VERSION 5.7 ;
  NOWIREEXTENSIONATPIN ON ;
  DIVIDERCHAR "/" ;
  BUSBITCHARS "[]" ;
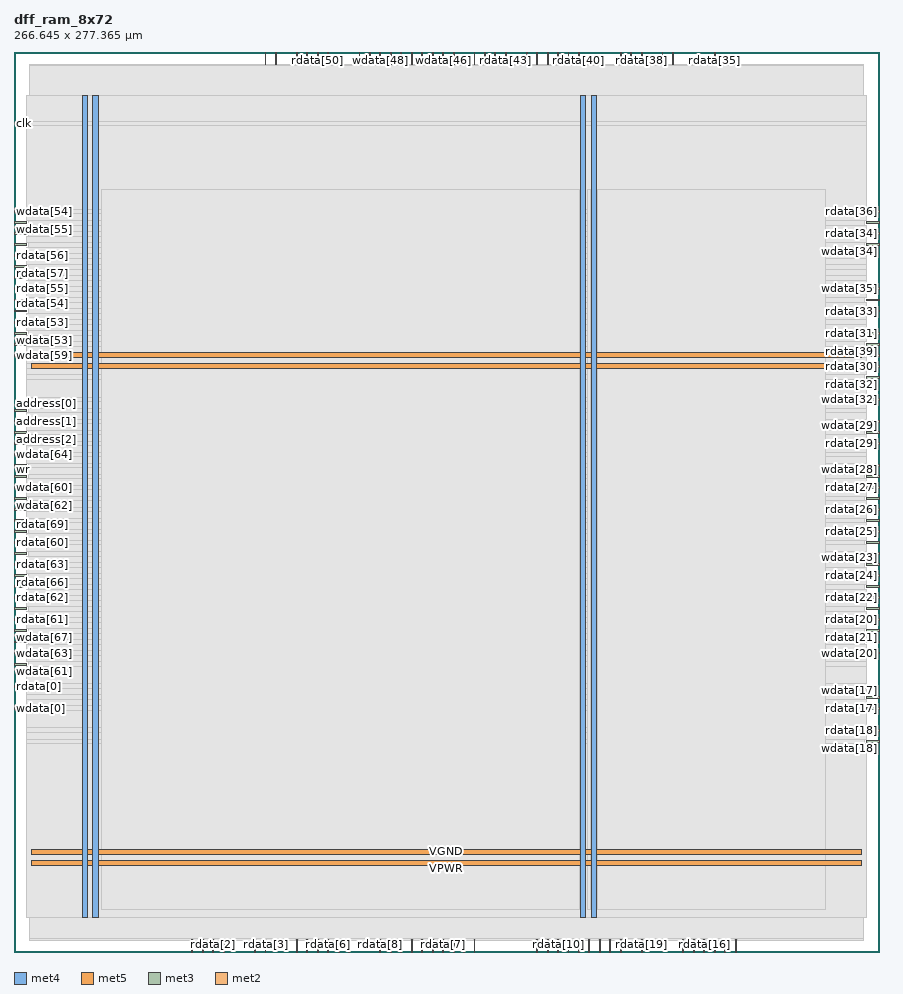
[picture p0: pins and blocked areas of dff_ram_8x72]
MACRO dff_ram_8x72
  CLASS BLOCK ;
  FOREIGN dff_ram_8x72 ;
  ORIGIN 0.000 0.000 ;
  SIZE 266.645 BY 277.365 ;
  PIN VGND
    DIRECTION INOUT ;
    USE GROUND ;
    PORT
      LAYER met4 ;
        RECT 24.340 10.640 25.940 264.080 ;
    END
    PORT
      LAYER met4 ;
        RECT 177.940 10.640 179.540 264.080 ;
    END
    PORT
      LAYER met5 ;
        RECT 5.280 30.030 261.060 31.630 ;
    END
    PORT
      LAYER met5 ;
        RECT 5.280 183.210 261.060 184.810 ;
    END
  END VGND
  PIN VPWR
    DIRECTION INOUT ;
    USE POWER ;
    PORT
      LAYER met4 ;
        RECT 21.040 10.640 22.640 264.080 ;
    END
    PORT
      LAYER met4 ;
        RECT 174.640 10.640 176.240 264.080 ;
    END
    PORT
      LAYER met5 ;
        RECT 5.280 26.730 261.060 28.330 ;
    END
    PORT
      LAYER met5 ;
        RECT 5.280 179.910 261.060 181.510 ;
    END
  END VPWR
  PIN address[0]
    DIRECTION INPUT ;
    USE SIGNAL ;
    ANTENNAGATEAREA 0.213000 ;
    PORT
      LAYER met3 ;
        RECT 0.000 166.640 4.000 167.240 ;
    END
  END address[0]
  PIN address[1]
    DIRECTION INPUT ;
    USE SIGNAL ;
    ANTENNAGATEAREA 0.159000 ;
    PORT
      LAYER met3 ;
        RECT 0.000 163.240 4.000 163.840 ;
    END
  END address[1]
  PIN address[2]
    DIRECTION INPUT ;
    USE SIGNAL ;
    ANTENNAGATEAREA 0.126000 ;
    PORT
      LAYER met3 ;
        RECT 0.000 159.840 4.000 160.440 ;
    END
  END address[2]
  PIN clk
    DIRECTION INPUT ;
    USE SIGNAL ;
    ANTENNAGATEAREA 0.852000 ;
    PORT
      LAYER met3 ;
        RECT 0.000 255.040 4.000 255.640 ;
    END
  END clk
  PIN rdata[0]
    DIRECTION OUTPUT TRISTATE ;
    USE SIGNAL ;
    ANTENNADIFFAREA 0.795200 ;
    PORT
      LAYER met3 ;
        RECT 0.000 81.640 4.000 82.240 ;
    END
  END rdata[0]
  PIN rdata[10]
    DIRECTION OUTPUT TRISTATE ;
    USE SIGNAL ;
    ANTENNADIFFAREA 0.795200 ;
    PORT
      LAYER met2 ;
        RECT 167.530 0.000 167.810 4.000 ;
    END
  END rdata[10]
  PIN rdata[11]
    DIRECTION OUTPUT TRISTATE ;
    USE SIGNAL ;
    ANTENNADIFFAREA 0.795200 ;
    PORT
      LAYER met2 ;
        RECT 177.190 0.000 177.470 4.000 ;
    END
  END rdata[11]
  PIN rdata[12]
    DIRECTION OUTPUT TRISTATE ;
    USE SIGNAL ;
    ANTENNADIFFAREA 0.795200 ;
    PORT
      LAYER met2 ;
        RECT 170.750 0.000 171.030 4.000 ;
    END
  END rdata[12]
  PIN rdata[13]
    DIRECTION OUTPUT TRISTATE ;
    USE SIGNAL ;
    ANTENNADIFFAREA 0.795200 ;
    PORT
      LAYER met2 ;
        RECT 219.050 0.000 219.330 4.000 ;
    END
  END rdata[13]
  PIN rdata[14]
    DIRECTION OUTPUT TRISTATE ;
    USE SIGNAL ;
    ANTENNADIFFAREA 0.795200 ;
    PORT
      LAYER met2 ;
        RECT 215.830 0.000 216.110 4.000 ;
    END
  END rdata[14]
  PIN rdata[15]
    DIRECTION OUTPUT TRISTATE ;
    USE SIGNAL ;
    ANTENNADIFFAREA 0.795200 ;
    PORT
      LAYER met2 ;
        RECT 173.970 0.000 174.250 4.000 ;
    END
  END rdata[15]
  PIN rdata[16]
    DIRECTION OUTPUT TRISTATE ;
    USE SIGNAL ;
    ANTENNADIFFAREA 0.795200 ;
    PORT
      LAYER met2 ;
        RECT 212.610 0.000 212.890 4.000 ;
    END
  END rdata[16]
  PIN rdata[17]
    DIRECTION OUTPUT TRISTATE ;
    USE SIGNAL ;
    ANTENNADIFFAREA 0.795200 ;
    PORT
      LAYER met3 ;
        RECT 262.645 74.840 266.645 75.440 ;
    END
  END rdata[17]
  PIN rdata[18]
    DIRECTION OUTPUT TRISTATE ;
    USE SIGNAL ;
    ANTENNADIFFAREA 0.795200 ;
    PORT
      LAYER met3 ;
        RECT 262.645 68.040 266.645 68.640 ;
    END
  END rdata[18]
  PIN rdata[19]
    DIRECTION OUTPUT TRISTATE ;
    USE SIGNAL ;
    ANTENNADIFFAREA 0.795200 ;
    PORT
      LAYER met2 ;
        RECT 193.290 0.000 193.570 4.000 ;
    END
  END rdata[19]
  PIN rdata[1]
    DIRECTION OUTPUT TRISTATE ;
    USE SIGNAL ;
    ANTENNADIFFAREA 0.795200 ;
    PORT
      LAYER met2 ;
        RECT 64.490 0.000 64.770 4.000 ;
    END
  END rdata[1]
  PIN rdata[20]
    DIRECTION OUTPUT TRISTATE ;
    USE SIGNAL ;
    ANTENNADIFFAREA 0.795200 ;
    PORT
      LAYER met3 ;
        RECT 262.645 102.040 266.645 102.640 ;
    END
  END rdata[20]
  PIN rdata[21]
    DIRECTION OUTPUT TRISTATE ;
    USE SIGNAL ;
    ANTENNADIFFAREA 0.445500 ;
    PORT
      LAYER met3 ;
        RECT 262.645 98.640 266.645 99.240 ;
    END
  END rdata[21]
  PIN rdata[22]
    DIRECTION OUTPUT TRISTATE ;
    USE SIGNAL ;
    ANTENNADIFFAREA 0.445500 ;
    PORT
      LAYER met3 ;
        RECT 262.645 108.840 266.645 109.440 ;
    END
  END rdata[22]
  PIN rdata[23]
    DIRECTION OUTPUT TRISTATE ;
    USE SIGNAL ;
    ANTENNADIFFAREA 0.445500 ;
    PORT
      LAYER met3 ;
        RECT 262.645 122.440 266.645 123.040 ;
    END
  END rdata[23]
  PIN rdata[24]
    DIRECTION OUTPUT TRISTATE ;
    USE SIGNAL ;
    ANTENNADIFFAREA 0.795200 ;
    PORT
      LAYER met3 ;
        RECT 262.645 115.640 266.645 116.240 ;
    END
  END rdata[24]
  PIN rdata[25]
    DIRECTION OUTPUT TRISTATE ;
    USE SIGNAL ;
    ANTENNADIFFAREA 0.795200 ;
    PORT
      LAYER met3 ;
        RECT 262.645 129.240 266.645 129.840 ;
    END
  END rdata[25]
  PIN rdata[26]
    DIRECTION OUTPUT TRISTATE ;
    USE SIGNAL ;
    ANTENNADIFFAREA 0.445500 ;
    PORT
      LAYER met3 ;
        RECT 262.645 136.040 266.645 136.640 ;
    END
  END rdata[26]
  PIN rdata[27]
    DIRECTION OUTPUT TRISTATE ;
    USE SIGNAL ;
    ANTENNADIFFAREA 0.795200 ;
    PORT
      LAYER met3 ;
        RECT 262.645 142.840 266.645 143.440 ;
    END
  END rdata[27]
  PIN rdata[28]
    DIRECTION OUTPUT TRISTATE ;
    USE SIGNAL ;
    ANTENNADIFFAREA 0.445500 ;
    PORT
      LAYER met3 ;
        RECT 262.645 149.640 266.645 150.240 ;
    END
  END rdata[28]
  PIN rdata[29]
    DIRECTION OUTPUT TRISTATE ;
    USE SIGNAL ;
    ANTENNADIFFAREA 0.445500 ;
    PORT
      LAYER met3 ;
        RECT 262.645 156.440 266.645 157.040 ;
    END
  END rdata[29]
  PIN rdata[2]
    DIRECTION OUTPUT TRISTATE ;
    USE SIGNAL ;
    ANTENNADIFFAREA 0.795200 ;
    PORT
      LAYER met2 ;
        RECT 61.270 0.000 61.550 4.000 ;
    END
  END rdata[2]
  PIN rdata[30]
    DIRECTION OUTPUT TRISTATE ;
    USE SIGNAL ;
    ANTENNADIFFAREA 0.795200 ;
    PORT
      LAYER met3 ;
        RECT 262.645 180.240 266.645 180.840 ;
    END
  END rdata[30]
  PIN rdata[31]
    DIRECTION OUTPUT TRISTATE ;
    USE SIGNAL ;
    ANTENNADIFFAREA 0.795200 ;
    PORT
      LAYER met3 ;
        RECT 262.645 190.440 266.645 191.040 ;
    END
  END rdata[31]
  PIN rdata[32]
    DIRECTION OUTPUT TRISTATE ;
    USE SIGNAL ;
    ANTENNADIFFAREA 0.445500 ;
    PORT
      LAYER met3 ;
        RECT 262.645 176.840 266.645 177.440 ;
    END
  END rdata[32]
  PIN rdata[33]
    DIRECTION OUTPUT TRISTATE ;
    USE SIGNAL ;
    ANTENNADIFFAREA 0.445500 ;
    PORT
      LAYER met3 ;
        RECT 262.645 197.240 266.645 197.840 ;
    END
  END rdata[33]
  PIN rdata[34]
    DIRECTION OUTPUT TRISTATE ;
    USE SIGNAL ;
    ANTENNADIFFAREA 0.795200 ;
    PORT
      LAYER met3 ;
        RECT 262.645 221.040 266.645 221.640 ;
    END
  END rdata[34]
  PIN rdata[35]
    DIRECTION OUTPUT TRISTATE ;
    USE SIGNAL ;
    ANTENNADIFFAREA 0.795200 ;
    PORT
      LAYER met2 ;
        RECT 215.830 273.365 216.110 277.365 ;
    END
  END rdata[35]
  PIN rdata[36]
    DIRECTION OUTPUT TRISTATE ;
    USE SIGNAL ;
    ANTENNADIFFAREA 0.445500 ;
    PORT
      LAYER met3 ;
        RECT 262.645 227.840 266.645 228.440 ;
    END
  END rdata[36]
  PIN rdata[37]
    DIRECTION OUTPUT TRISTATE ;
    USE SIGNAL ;
    ANTENNADIFFAREA 0.795200 ;
    PORT
      LAYER met2 ;
        RECT 202.950 273.365 203.230 277.365 ;
    END
  END rdata[37]
  PIN rdata[38]
    DIRECTION OUTPUT TRISTATE ;
    USE SIGNAL ;
    ANTENNADIFFAREA 0.795200 ;
    PORT
      LAYER met2 ;
        RECT 193.290 273.365 193.570 277.365 ;
    END
  END rdata[38]
  PIN rdata[39]
    DIRECTION OUTPUT TRISTATE ;
    USE SIGNAL ;
    ANTENNADIFFAREA 0.445500 ;
    PORT
      LAYER met3 ;
        RECT 262.645 187.040 266.645 187.640 ;
    END
  END rdata[39]
  PIN rdata[3]
    DIRECTION OUTPUT TRISTATE ;
    USE SIGNAL ;
    ANTENNADIFFAREA 0.795200 ;
    PORT
      LAYER met2 ;
        RECT 77.370 0.000 77.650 4.000 ;
    END
  END rdata[3]
  PIN rdata[40]
    DIRECTION OUTPUT TRISTATE ;
    USE SIGNAL ;
    ANTENNADIFFAREA 0.795200 ;
    PORT
      LAYER met2 ;
        RECT 173.970 273.365 174.250 277.365 ;
    END
  END rdata[40]
  PIN rdata[41]
    DIRECTION OUTPUT TRISTATE ;
    USE SIGNAL ;
    ANTENNADIFFAREA 0.795200 ;
    PORT
      LAYER met2 ;
        RECT 157.870 273.365 158.150 277.365 ;
    END
  END rdata[41]
  PIN rdata[42]
    DIRECTION OUTPUT TRISTATE ;
    USE SIGNAL ;
    ANTENNADIFFAREA 0.795200 ;
    PORT
      LAYER met2 ;
        RECT 170.750 273.365 171.030 277.365 ;
    END
  END rdata[42]
  PIN rdata[43]
    DIRECTION OUTPUT TRISTATE ;
    USE SIGNAL ;
    ANTENNADIFFAREA 0.795200 ;
    PORT
      LAYER met2 ;
        RECT 151.430 273.365 151.710 277.365 ;
    END
  END rdata[43]
  PIN rdata[44]
    DIRECTION OUTPUT TRISTATE ;
    USE SIGNAL ;
    ANTENNADIFFAREA 0.795200 ;
    PORT
      LAYER met2 ;
        RECT 148.210 273.365 148.490 277.365 ;
    END
  END rdata[44]
  PIN rdata[45]
    DIRECTION OUTPUT TRISTATE ;
    USE SIGNAL ;
    ANTENNADIFFAREA 0.795200 ;
    PORT
      LAYER met2 ;
        RECT 128.890 273.365 129.170 277.365 ;
    END
  END rdata[45]
  PIN rdata[46]
    DIRECTION OUTPUT TRISTATE ;
    USE SIGNAL ;
    ANTENNADIFFAREA 0.795200 ;
    PORT
      LAYER met2 ;
        RECT 135.330 273.365 135.610 277.365 ;
    END
  END rdata[46]
  PIN rdata[47]
    DIRECTION OUTPUT TRISTATE ;
    USE SIGNAL ;
    ANTENNADIFFAREA 0.795200 ;
    PORT
      LAYER met2 ;
        RECT 122.450 273.365 122.730 277.365 ;
    END
  END rdata[47]
  PIN rdata[48]
    DIRECTION OUTPUT TRISTATE ;
    USE SIGNAL ;
    ANTENNADIFFAREA 0.795200 ;
    PORT
      LAYER met2 ;
        RECT 119.230 273.365 119.510 277.365 ;
    END
  END rdata[48]
  PIN rdata[49]
    DIRECTION OUTPUT TRISTATE ;
    USE SIGNAL ;
    ANTENNADIFFAREA 0.795200 ;
    PORT
      LAYER met2 ;
        RECT 109.570 273.365 109.850 277.365 ;
    END
  END rdata[49]
  PIN rdata[4]
    DIRECTION OUTPUT TRISTATE ;
    USE SIGNAL ;
    ANTENNADIFFAREA 0.795200 ;
    PORT
      LAYER met2 ;
        RECT 87.030 0.000 87.310 4.000 ;
    END
  END rdata[4]
  PIN rdata[50]
    DIRECTION OUTPUT TRISTATE ;
    USE SIGNAL ;
    ANTENNADIFFAREA 0.795200 ;
    PORT
      LAYER met2 ;
        RECT 93.470 273.365 93.750 277.365 ;
    END
  END rdata[50]
  PIN rdata[51]
    DIRECTION OUTPUT TRISTATE ;
    USE SIGNAL ;
    ANTENNADIFFAREA 0.795200 ;
    PORT
      LAYER met2 ;
        RECT 77.370 273.365 77.650 277.365 ;
    END
  END rdata[51]
  PIN rdata[52]
    DIRECTION OUTPUT TRISTATE ;
    USE SIGNAL ;
    ANTENNADIFFAREA 0.795200 ;
    PORT
      LAYER met2 ;
        RECT 90.250 273.365 90.530 277.365 ;
    END
  END rdata[52]
  PIN rdata[53]
    DIRECTION OUTPUT TRISTATE ;
    USE SIGNAL ;
    ANTENNADIFFAREA 0.795200 ;
    PORT
      LAYER met3 ;
        RECT 0.000 193.840 4.000 194.440 ;
    END
  END rdata[53]
  PIN rdata[54]
    DIRECTION OUTPUT TRISTATE ;
    USE SIGNAL ;
    ANTENNADIFFAREA 0.795200 ;
    PORT
      LAYER met3 ;
        RECT 0.000 197.240 4.000 197.840 ;
    END
  END rdata[54]
  PIN rdata[55]
    DIRECTION OUTPUT TRISTATE ;
    USE SIGNAL ;
    ANTENNADIFFAREA 0.795200 ;
    PORT
      LAYER met3 ;
        RECT 0.000 204.040 4.000 204.640 ;
    END
  END rdata[55]
  PIN rdata[56]
    DIRECTION OUTPUT TRISTATE ;
    USE SIGNAL ;
    ANTENNADIFFAREA 0.795200 ;
    PORT
      LAYER met3 ;
        RECT 0.000 214.240 4.000 214.840 ;
    END
  END rdata[56]
  PIN rdata[57]
    DIRECTION OUTPUT TRISTATE ;
    USE SIGNAL ;
    ANTENNADIFFAREA 0.795200 ;
    PORT
      LAYER met3 ;
        RECT 0.000 210.840 4.000 211.440 ;
    END
  END rdata[57]
  PIN rdata[58]
    DIRECTION OUTPUT TRISTATE ;
    USE SIGNAL ;
    ANTENNADIFFAREA 0.795200 ;
    PORT
      LAYER met3 ;
        RECT 0.000 207.440 4.000 208.040 ;
    END
  END rdata[58]
  PIN rdata[59]
    DIRECTION OUTPUT TRISTATE ;
    USE SIGNAL ;
    ANTENNADIFFAREA 0.795200 ;
    PORT
      LAYER met3 ;
        RECT 0.000 200.640 4.000 201.240 ;
    END
  END rdata[59]
  PIN rdata[5]
    DIRECTION OUTPUT TRISTATE ;
    USE SIGNAL ;
    ANTENNADIFFAREA 0.795200 ;
    PORT
      LAYER met2 ;
        RECT 99.910 0.000 100.190 4.000 ;
    END
  END rdata[5]
  PIN rdata[60]
    DIRECTION OUTPUT TRISTATE ;
    USE SIGNAL ;
    ANTENNADIFFAREA 0.795200 ;
    PORT
      LAYER met3 ;
        RECT 0.000 125.840 4.000 126.440 ;
    END
  END rdata[60]
  PIN rdata[61]
    DIRECTION OUTPUT TRISTATE ;
    USE SIGNAL ;
    ANTENNADIFFAREA 0.795200 ;
    PORT
      LAYER met3 ;
        RECT 0.000 102.040 4.000 102.640 ;
    END
  END rdata[61]
  PIN rdata[62]
    DIRECTION OUTPUT TRISTATE ;
    USE SIGNAL ;
    ANTENNADIFFAREA 0.795200 ;
    PORT
      LAYER met3 ;
        RECT 0.000 108.840 4.000 109.440 ;
    END
  END rdata[62]
  PIN rdata[63]
    DIRECTION OUTPUT TRISTATE ;
    USE SIGNAL ;
    ANTENNADIFFAREA 0.795200 ;
    PORT
      LAYER met3 ;
        RECT 0.000 119.040 4.000 119.640 ;
    END
  END rdata[63]
  PIN rdata[64]
    DIRECTION OUTPUT TRISTATE ;
    USE SIGNAL ;
    ANTENNADIFFAREA 0.795200 ;
    PORT
      LAYER met3 ;
        RECT 0.000 122.440 4.000 123.040 ;
    END
  END rdata[64]
  PIN rdata[65]
    DIRECTION OUTPUT TRISTATE ;
    USE SIGNAL ;
    ANTENNADIFFAREA 0.795200 ;
    PORT
      LAYER met3 ;
        RECT 0.000 112.240 4.000 112.840 ;
    END
  END rdata[65]
  PIN rdata[66]
    DIRECTION OUTPUT TRISTATE ;
    USE SIGNAL ;
    ANTENNADIFFAREA 0.795200 ;
    PORT
      LAYER met3 ;
        RECT 0.000 115.640 4.000 116.240 ;
    END
  END rdata[66]
  PIN rdata[67]
    DIRECTION OUTPUT TRISTATE ;
    USE SIGNAL ;
    ANTENNADIFFAREA 0.795200 ;
    PORT
      LAYER met3 ;
        RECT 0.000 132.640 4.000 133.240 ;
    END
  END rdata[67]
  PIN rdata[68]
    DIRECTION OUTPUT TRISTATE ;
    USE SIGNAL ;
    ANTENNADIFFAREA 0.795200 ;
    PORT
      LAYER met3 ;
        RECT 0.000 105.440 4.000 106.040 ;
    END
  END rdata[68]
  PIN rdata[69]
    DIRECTION OUTPUT TRISTATE ;
    USE SIGNAL ;
    ANTENNADIFFAREA 0.795200 ;
    PORT
      LAYER met3 ;
        RECT 0.000 129.240 4.000 129.840 ;
    END
  END rdata[69]
  PIN rdata[6]
    DIRECTION OUTPUT TRISTATE ;
    USE SIGNAL ;
    ANTENNADIFFAREA 0.795200 ;
    PORT
      LAYER met2 ;
        RECT 96.690 0.000 96.970 4.000 ;
    END
  END rdata[6]
  PIN rdata[70]
    DIRECTION OUTPUT TRISTATE ;
    USE SIGNAL ;
    ANTENNADIFFAREA 0.795200 ;
    PORT
      LAYER met2 ;
        RECT 125.670 0.000 125.950 4.000 ;
    END
  END rdata[70]
  PIN rdata[71]
    DIRECTION OUTPUT TRISTATE ;
    USE SIGNAL ;
    ANTENNADIFFAREA 0.795200 ;
    PORT
      LAYER met2 ;
        RECT 141.770 0.000 142.050 4.000 ;
    END
  END rdata[71]
  PIN rdata[7]
    DIRECTION OUTPUT TRISTATE ;
    USE SIGNAL ;
    ANTENNADIFFAREA 0.795200 ;
    PORT
      LAYER met2 ;
        RECT 132.110 0.000 132.390 4.000 ;
    END
  END rdata[7]
  PIN rdata[8]
    DIRECTION OUTPUT TRISTATE ;
    USE SIGNAL ;
    ANTENNADIFFAREA 0.795200 ;
    PORT
      LAYER met2 ;
        RECT 112.790 0.000 113.070 4.000 ;
    END
  END rdata[8]
  PIN rdata[9]
    DIRECTION OUTPUT TRISTATE ;
    USE SIGNAL ;
    ANTENNADIFFAREA 0.795200 ;
    PORT
      LAYER met2 ;
        RECT 135.330 0.000 135.610 4.000 ;
    END
  END rdata[9]
  PIN wdata[0]
    DIRECTION INPUT ;
    USE SIGNAL ;
    ANTENNAGATEAREA 0.196500 ;
    PORT
      LAYER met3 ;
        RECT 0.000 74.840 4.000 75.440 ;
    END
  END wdata[0]
  PIN wdata[10]
    DIRECTION INPUT ;
    USE SIGNAL ;
    ANTENNAGATEAREA 0.196500 ;
    PORT
      LAYER met2 ;
        RECT 161.090 0.000 161.370 4.000 ;
    END
  END wdata[10]
  PIN wdata[11]
    DIRECTION INPUT ;
    USE SIGNAL ;
    ANTENNAGATEAREA 0.196500 ;
    PORT
      LAYER met2 ;
        RECT 180.410 0.000 180.690 4.000 ;
    END
  END wdata[11]
  PIN wdata[12]
    DIRECTION INPUT ;
    USE SIGNAL ;
    ANTENNAGATEAREA 0.196500 ;
    PORT
      LAYER met2 ;
        RECT 164.310 0.000 164.590 4.000 ;
    END
  END wdata[12]
  PIN wdata[13]
    DIRECTION INPUT ;
    USE SIGNAL ;
    ANTENNAGATEAREA 0.196500 ;
    PORT
      LAYER met2 ;
        RECT 222.270 0.000 222.550 4.000 ;
    END
  END wdata[13]
  PIN wdata[14]
    DIRECTION INPUT ;
    USE SIGNAL ;
    ANTENNAGATEAREA 0.196500 ;
    PORT
      LAYER met2 ;
        RECT 209.390 0.000 209.670 4.000 ;
    END
  END wdata[14]
  PIN wdata[15]
    DIRECTION INPUT ;
    USE SIGNAL ;
    ANTENNAGATEAREA 0.196500 ;
    PORT
      LAYER met2 ;
        RECT 186.850 0.000 187.130 4.000 ;
    END
  END wdata[15]
  PIN wdata[16]
    DIRECTION INPUT ;
    USE SIGNAL ;
    ANTENNAGATEAREA 0.196500 ;
    PORT
      LAYER met2 ;
        RECT 206.170 0.000 206.450 4.000 ;
    END
  END wdata[16]
  PIN wdata[17]
    DIRECTION INPUT ;
    USE SIGNAL ;
    ANTENNAGATEAREA 0.196500 ;
    PORT
      LAYER met3 ;
        RECT 262.645 78.240 266.645 78.840 ;
    END
  END wdata[17]
  PIN wdata[18]
    DIRECTION INPUT ;
    USE SIGNAL ;
    ANTENNAGATEAREA 0.196500 ;
    PORT
      LAYER met3 ;
        RECT 262.645 64.640 266.645 65.240 ;
    END
  END wdata[18]
  PIN wdata[19]
    DIRECTION INPUT ;
    USE SIGNAL ;
    ANTENNAGATEAREA 0.196500 ;
    PORT
      LAYER met2 ;
        RECT 183.630 0.000 183.910 4.000 ;
    END
  END wdata[19]
  PIN wdata[1]
    DIRECTION INPUT ;
    USE SIGNAL ;
    ANTENNAGATEAREA 0.196500 ;
    PORT
      LAYER met2 ;
        RECT 58.050 0.000 58.330 4.000 ;
    END
  END wdata[1]
  PIN wdata[20]
    DIRECTION INPUT ;
    USE SIGNAL ;
    ANTENNAGATEAREA 0.196500 ;
    PORT
      LAYER met3 ;
        RECT 262.645 91.840 266.645 92.440 ;
    END
  END wdata[20]
  PIN wdata[21]
    DIRECTION INPUT ;
    USE SIGNAL ;
    ANTENNAGATEAREA 0.196500 ;
    PORT
      LAYER met3 ;
        RECT 262.645 95.240 266.645 95.840 ;
    END
  END wdata[21]
  PIN wdata[22]
    DIRECTION INPUT ;
    USE SIGNAL ;
    ANTENNAGATEAREA 0.196500 ;
    PORT
      LAYER met3 ;
        RECT 262.645 105.440 266.645 106.040 ;
    END
  END wdata[22]
  PIN wdata[23]
    DIRECTION INPUT ;
    USE SIGNAL ;
    ANTENNAGATEAREA 0.196500 ;
    PORT
      LAYER met3 ;
        RECT 262.645 119.040 266.645 119.640 ;
    END
  END wdata[23]
  PIN wdata[24]
    DIRECTION INPUT ;
    USE SIGNAL ;
    ANTENNAGATEAREA 0.196500 ;
    PORT
      LAYER met3 ;
        RECT 262.645 112.240 266.645 112.840 ;
    END
  END wdata[24]
  PIN wdata[25]
    DIRECTION INPUT ;
    USE SIGNAL ;
    ANTENNAGATEAREA 0.196500 ;
    PORT
      LAYER met3 ;
        RECT 262.645 125.840 266.645 126.440 ;
    END
  END wdata[25]
  PIN wdata[26]
    DIRECTION INPUT ;
    USE SIGNAL ;
    ANTENNAGATEAREA 0.196500 ;
    PORT
      LAYER met3 ;
        RECT 262.645 132.640 266.645 133.240 ;
    END
  END wdata[26]
  PIN wdata[27]
    DIRECTION INPUT ;
    USE SIGNAL ;
    ANTENNAGATEAREA 0.196500 ;
    PORT
      LAYER met3 ;
        RECT 262.645 139.440 266.645 140.040 ;
    END
  END wdata[27]
  PIN wdata[28]
    DIRECTION INPUT ;
    USE SIGNAL ;
    ANTENNAGATEAREA 0.196500 ;
    PORT
      LAYER met3 ;
        RECT 262.645 146.240 266.645 146.840 ;
    END
  END wdata[28]
  PIN wdata[29]
    DIRECTION INPUT ;
    USE SIGNAL ;
    ANTENNAGATEAREA 0.196500 ;
    PORT
      LAYER met3 ;
        RECT 262.645 159.840 266.645 160.440 ;
    END
  END wdata[29]
  PIN wdata[2]
    DIRECTION INPUT ;
    USE SIGNAL ;
    ANTENNAGATEAREA 0.196500 ;
    PORT
      LAYER met2 ;
        RECT 54.830 0.000 55.110 4.000 ;
    END
  END wdata[2]
  PIN wdata[30]
    DIRECTION INPUT ;
    USE SIGNAL ;
    ANTENNAGATEAREA 0.196500 ;
    PORT
      LAYER met3 ;
        RECT 262.645 163.240 266.645 163.840 ;
    END
  END wdata[30]
  PIN wdata[31]
    DIRECTION INPUT ;
    USE SIGNAL ;
    ANTENNAGATEAREA 0.196500 ;
    PORT
      LAYER met3 ;
        RECT 262.645 183.640 266.645 184.240 ;
    END
  END wdata[31]
  PIN wdata[32]
    DIRECTION INPUT ;
    USE SIGNAL ;
    ANTENNAGATEAREA 0.196500 ;
    PORT
      LAYER met3 ;
        RECT 262.645 170.040 266.645 170.640 ;
    END
  END wdata[32]
  PIN wdata[33]
    DIRECTION INPUT ;
    USE SIGNAL ;
    ANTENNAGATEAREA 0.196500 ;
    PORT
      LAYER met3 ;
        RECT 262.645 200.640 266.645 201.240 ;
    END
  END wdata[33]
  PIN wdata[34]
    DIRECTION INPUT ;
    USE SIGNAL ;
    ANTENNAGATEAREA 0.196500 ;
    PORT
      LAYER met3 ;
        RECT 262.645 217.640 266.645 218.240 ;
    END
  END wdata[34]
  PIN wdata[35]
    DIRECTION INPUT ;
    USE SIGNAL ;
    ANTENNAGATEAREA 0.196500 ;
    PORT
      LAYER met3 ;
        RECT 262.645 204.040 266.645 204.640 ;
    END
  END wdata[35]
  PIN wdata[36]
    DIRECTION INPUT ;
    USE SIGNAL ;
    ANTENNAGATEAREA 0.196500 ;
    PORT
      LAYER met3 ;
        RECT 262.645 224.440 266.645 225.040 ;
    END
  END wdata[36]
  PIN wdata[37]
    DIRECTION INPUT ;
    USE SIGNAL ;
    ANTENNAGATEAREA 0.196500 ;
    PORT
      LAYER met2 ;
        RECT 199.730 273.365 200.010 277.365 ;
    END
  END wdata[37]
  PIN wdata[38]
    DIRECTION INPUT ;
    USE SIGNAL ;
    ANTENNAGATEAREA 0.196500 ;
    PORT
      LAYER met2 ;
        RECT 190.070 273.365 190.350 277.365 ;
    END
  END wdata[38]
  PIN wdata[39]
    DIRECTION INPUT ;
    USE SIGNAL ;
    ANTENNAGATEAREA 0.196500 ;
    PORT
      LAYER met2 ;
        RECT 186.850 273.365 187.130 277.365 ;
    END
  END wdata[39]
  PIN wdata[3]
    DIRECTION INPUT ;
    USE SIGNAL ;
    ANTENNAGATEAREA 0.196500 ;
    PORT
      LAYER met2 ;
        RECT 74.150 0.000 74.430 4.000 ;
    END
  END wdata[3]
  PIN wdata[40]
    DIRECTION INPUT ;
    USE SIGNAL ;
    ANTENNAGATEAREA 0.196500 ;
    PORT
      LAYER met2 ;
        RECT 167.530 273.365 167.810 277.365 ;
    END
  END wdata[40]
  PIN wdata[41]
    DIRECTION INPUT ;
    USE SIGNAL ;
    ANTENNAGATEAREA 0.196500 ;
    PORT
      LAYER met2 ;
        RECT 161.090 273.365 161.370 277.365 ;
    END
  END wdata[41]
  PIN wdata[42]
    DIRECTION INPUT ;
    USE SIGNAL ;
    ANTENNAGATEAREA 0.196500 ;
    PORT
      LAYER met2 ;
        RECT 164.310 273.365 164.590 277.365 ;
    END
  END wdata[42]
  PIN wdata[43]
    DIRECTION INPUT ;
    USE SIGNAL ;
    ANTENNAGATEAREA 0.196500 ;
    PORT
      LAYER met2 ;
        RECT 144.990 273.365 145.270 277.365 ;
    END
  END wdata[43]
  PIN wdata[44]
    DIRECTION INPUT ;
    USE SIGNAL ;
    ANTENNAGATEAREA 0.196500 ;
    PORT
      LAYER met2 ;
        RECT 141.770 273.365 142.050 277.365 ;
    END
  END wdata[44]
  PIN wdata[45]
    DIRECTION INPUT ;
    USE SIGNAL ;
    ANTENNAGATEAREA 0.196500 ;
    PORT
      LAYER met2 ;
        RECT 125.670 273.365 125.950 277.365 ;
    END
  END wdata[45]
  PIN wdata[46]
    DIRECTION INPUT ;
    USE SIGNAL ;
    ANTENNAGATEAREA 0.196500 ;
    PORT
      LAYER met2 ;
        RECT 132.110 273.365 132.390 277.365 ;
    END
  END wdata[46]
  PIN wdata[47]
    DIRECTION INPUT ;
    USE SIGNAL ;
    ANTENNAGATEAREA 0.196500 ;
    PORT
      LAYER met2 ;
        RECT 116.010 273.365 116.290 277.365 ;
    END
  END wdata[47]
  PIN wdata[48]
    DIRECTION INPUT ;
    USE SIGNAL ;
    ANTENNAGATEAREA 0.196500 ;
    PORT
      LAYER met2 ;
        RECT 112.790 273.365 113.070 277.365 ;
    END
  END wdata[48]
  PIN wdata[49]
    DIRECTION INPUT ;
    USE SIGNAL ;
    ANTENNAGATEAREA 0.196500 ;
    PORT
      LAYER met2 ;
        RECT 106.350 273.365 106.630 277.365 ;
    END
  END wdata[49]
  PIN wdata[4]
    DIRECTION INPUT ;
    USE SIGNAL ;
    ANTENNAGATEAREA 0.196500 ;
    PORT
      LAYER met2 ;
        RECT 90.250 0.000 90.530 4.000 ;
    END
  END wdata[4]
  PIN wdata[50]
    DIRECTION INPUT ;
    USE SIGNAL ;
    ANTENNAGATEAREA 0.196500 ;
    PORT
      LAYER met2 ;
        RECT 96.690 273.365 96.970 277.365 ;
    END
  END wdata[50]
  PIN wdata[51]
    DIRECTION INPUT ;
    USE SIGNAL ;
    ANTENNAGATEAREA 0.196500 ;
    PORT
      LAYER met2 ;
        RECT 80.590 273.365 80.870 277.365 ;
    END
  END wdata[51]
  PIN wdata[52]
    DIRECTION INPUT ;
    USE SIGNAL ;
    ANTENNAGATEAREA 0.196500 ;
    PORT
      LAYER met2 ;
        RECT 87.030 273.365 87.310 277.365 ;
    END
  END wdata[52]
  PIN wdata[53]
    DIRECTION INPUT ;
    USE SIGNAL ;
    ANTENNAGATEAREA 0.196500 ;
    PORT
      LAYER met3 ;
        RECT 0.000 190.440 4.000 191.040 ;
    END
  END wdata[53]
  PIN wdata[54]
    DIRECTION INPUT ;
    USE SIGNAL ;
    ANTENNAGATEAREA 0.196500 ;
    PORT
      LAYER met3 ;
        RECT 0.000 227.840 4.000 228.440 ;
    END
  END wdata[54]
  PIN wdata[55]
    DIRECTION INPUT ;
    USE SIGNAL ;
    ANTENNAGATEAREA 0.196500 ;
    PORT
      LAYER met3 ;
        RECT 0.000 224.440 4.000 225.040 ;
    END
  END wdata[55]
  PIN wdata[56]
    DIRECTION INPUT ;
    USE SIGNAL ;
    ANTENNAGATEAREA 0.196500 ;
    PORT
      LAYER met3 ;
        RECT 0.000 217.640 4.000 218.240 ;
    END
  END wdata[56]
  PIN wdata[57]
    DIRECTION INPUT ;
    USE SIGNAL ;
    ANTENNAGATEAREA 0.196500 ;
    PORT
      LAYER met3 ;
        RECT 0.000 221.040 4.000 221.640 ;
    END
  END wdata[57]
  PIN wdata[58]
    DIRECTION INPUT ;
    USE SIGNAL ;
    ANTENNAGATEAREA 0.196500 ;
    PORT
      LAYER met3 ;
        RECT 0.000 187.040 4.000 187.640 ;
    END
  END wdata[58]
  PIN wdata[59]
    DIRECTION INPUT ;
    USE SIGNAL ;
    ANTENNAGATEAREA 0.196500 ;
    PORT
      LAYER met3 ;
        RECT 0.000 183.640 4.000 184.240 ;
    END
  END wdata[59]
  PIN wdata[5]
    DIRECTION INPUT ;
    USE SIGNAL ;
    ANTENNAGATEAREA 0.196500 ;
    PORT
      LAYER met2 ;
        RECT 93.470 0.000 93.750 4.000 ;
    END
  END wdata[5]
  PIN wdata[60]
    DIRECTION INPUT ;
    USE SIGNAL ;
    ANTENNAGATEAREA 0.196500 ;
    PORT
      LAYER met3 ;
        RECT 0.000 142.840 4.000 143.440 ;
    END
  END wdata[60]
  PIN wdata[61]
    DIRECTION INPUT ;
    USE SIGNAL ;
    ANTENNAGATEAREA 0.196500 ;
    PORT
      LAYER met3 ;
        RECT 0.000 88.440 4.000 89.040 ;
    END
  END wdata[61]
  PIN wdata[62]
    DIRECTION INPUT ;
    USE SIGNAL ;
    ANTENNAGATEAREA 0.196500 ;
    PORT
      LAYER met3 ;
        RECT 0.000 139.440 4.000 140.040 ;
    END
  END wdata[62]
  PIN wdata[63]
    DIRECTION INPUT ;
    USE SIGNAL ;
    ANTENNAGATEAREA 0.196500 ;
    PORT
      LAYER met3 ;
        RECT 0.000 91.840 4.000 92.440 ;
    END
  END wdata[63]
  PIN wdata[64]
    DIRECTION INPUT ;
    USE SIGNAL ;
    ANTENNAGATEAREA 0.196500 ;
    PORT
      LAYER met3 ;
        RECT 0.000 153.040 4.000 153.640 ;
    END
  END wdata[64]
  PIN wdata[65]
    DIRECTION INPUT ;
    USE SIGNAL ;
    ANTENNAGATEAREA 0.196500 ;
    PORT
      LAYER met3 ;
        RECT 0.000 149.640 4.000 150.240 ;
    END
  END wdata[65]
  PIN wdata[66]
    DIRECTION INPUT ;
    USE SIGNAL ;
    ANTENNAGATEAREA 0.196500 ;
    PORT
      LAYER met3 ;
        RECT 0.000 95.240 4.000 95.840 ;
    END
  END wdata[66]
  PIN wdata[67]
    DIRECTION INPUT ;
    USE SIGNAL ;
    ANTENNAGATEAREA 0.196500 ;
    PORT
      LAYER met3 ;
        RECT 0.000 98.640 4.000 99.240 ;
    END
  END wdata[67]
  PIN wdata[68]
    DIRECTION INPUT ;
    USE SIGNAL ;
    ANTENNAGATEAREA 0.126000 ;
    PORT
      LAYER met3 ;
        RECT 0.000 156.440 4.000 157.040 ;
    END
  END wdata[68]
  PIN wdata[69]
    DIRECTION INPUT ;
    USE SIGNAL ;
    ANTENNAGATEAREA 0.196500 ;
    PORT
      LAYER met3 ;
        RECT 0.000 136.040 4.000 136.640 ;
    END
  END wdata[69]
  PIN wdata[6]
    DIRECTION INPUT ;
    USE SIGNAL ;
    ANTENNAGATEAREA 0.196500 ;
    PORT
      LAYER met2 ;
        RECT 103.130 0.000 103.410 4.000 ;
    END
  END wdata[6]
  PIN wdata[70]
    DIRECTION INPUT ;
    USE SIGNAL ;
    ANTENNAGATEAREA 0.196500 ;
    PORT
      LAYER met2 ;
        RECT 119.230 0.000 119.510 4.000 ;
    END
  END wdata[70]
  PIN wdata[71]
    DIRECTION INPUT ;
    USE SIGNAL ;
    ANTENNAGATEAREA 0.196500 ;
    PORT
      LAYER met2 ;
        RECT 122.450 0.000 122.730 4.000 ;
    END
  END wdata[71]
  PIN wdata[7]
    DIRECTION INPUT ;
    USE SIGNAL ;
    ANTENNAGATEAREA 0.196500 ;
    PORT
      LAYER met2 ;
        RECT 128.890 0.000 129.170 4.000 ;
    END
  END wdata[7]
  PIN wdata[8]
    DIRECTION INPUT ;
    USE SIGNAL ;
    ANTENNAGATEAREA 0.196500 ;
    PORT
      LAYER met2 ;
        RECT 116.010 0.000 116.290 4.000 ;
    END
  END wdata[8]
  PIN wdata[9]
    DIRECTION INPUT ;
    USE SIGNAL ;
    ANTENNAGATEAREA 0.196500 ;
    PORT
      LAYER met2 ;
        RECT 138.550 0.000 138.830 4.000 ;
    END
  END wdata[9]
  PIN wr
    DIRECTION INPUT ;
    USE SIGNAL ;
    ANTENNAGATEAREA 0.126000 ;
    PORT
      LAYER met3 ;
        RECT 0.000 146.240 4.000 146.840 ;
    END
  END wr
  OBS
      LAYER li1 ;
        RECT 5.520 10.795 260.820 263.925 ;
      LAYER met1 ;
        RECT 4.670 10.240 261.670 264.080 ;
      LAYER met2 ;
        RECT 4.690 273.085 77.090 273.365 ;
        RECT 77.930 273.085 80.310 273.365 ;
        RECT 81.150 273.085 86.750 273.365 ;
        RECT 87.590 273.085 89.970 273.365 ;
        RECT 90.810 273.085 93.190 273.365 ;
        RECT 94.030 273.085 96.410 273.365 ;
        RECT 97.250 273.085 106.070 273.365 ;
        RECT 106.910 273.085 109.290 273.365 ;
        RECT 110.130 273.085 112.510 273.365 ;
        RECT 113.350 273.085 115.730 273.365 ;
        RECT 116.570 273.085 118.950 273.365 ;
        RECT 119.790 273.085 122.170 273.365 ;
        RECT 123.010 273.085 125.390 273.365 ;
        RECT 126.230 273.085 128.610 273.365 ;
        RECT 129.450 273.085 131.830 273.365 ;
        RECT 132.670 273.085 135.050 273.365 ;
        RECT 135.890 273.085 141.490 273.365 ;
        RECT 142.330 273.085 144.710 273.365 ;
        RECT 145.550 273.085 147.930 273.365 ;
        RECT 148.770 273.085 151.150 273.365 ;
        RECT 151.990 273.085 157.590 273.365 ;
        RECT 158.430 273.085 160.810 273.365 ;
        RECT 161.650 273.085 164.030 273.365 ;
        RECT 164.870 273.085 167.250 273.365 ;
        RECT 168.090 273.085 170.470 273.365 ;
        RECT 171.310 273.085 173.690 273.365 ;
        RECT 174.530 273.085 186.570 273.365 ;
        RECT 187.410 273.085 189.790 273.365 ;
        RECT 190.630 273.085 193.010 273.365 ;
        RECT 193.850 273.085 199.450 273.365 ;
        RECT 200.290 273.085 202.670 273.365 ;
        RECT 203.510 273.085 215.550 273.365 ;
        RECT 216.390 273.085 261.650 273.365 ;
        RECT 4.690 4.280 261.650 273.085 ;
        RECT 4.690 3.670 54.550 4.280 ;
        RECT 55.390 3.670 57.770 4.280 ;
        RECT 58.610 3.670 60.990 4.280 ;
        RECT 61.830 3.670 64.210 4.280 ;
        RECT 65.050 3.670 73.870 4.280 ;
        RECT 74.710 3.670 77.090 4.280 ;
        RECT 77.930 3.670 86.750 4.280 ;
        RECT 87.590 3.670 89.970 4.280 ;
        RECT 90.810 3.670 93.190 4.280 ;
        RECT 94.030 3.670 96.410 4.280 ;
        RECT 97.250 3.670 99.630 4.280 ;
        RECT 100.470 3.670 102.850 4.280 ;
        RECT 103.690 3.670 112.510 4.280 ;
        RECT 113.350 3.670 115.730 4.280 ;
        RECT 116.570 3.670 118.950 4.280 ;
        RECT 119.790 3.670 122.170 4.280 ;
        RECT 123.010 3.670 125.390 4.280 ;
        RECT 126.230 3.670 128.610 4.280 ;
        RECT 129.450 3.670 131.830 4.280 ;
        RECT 132.670 3.670 135.050 4.280 ;
        RECT 135.890 3.670 138.270 4.280 ;
        RECT 139.110 3.670 141.490 4.280 ;
        RECT 142.330 3.670 160.810 4.280 ;
        RECT 161.650 3.670 164.030 4.280 ;
        RECT 164.870 3.670 167.250 4.280 ;
        RECT 168.090 3.670 170.470 4.280 ;
        RECT 171.310 3.670 173.690 4.280 ;
        RECT 174.530 3.670 176.910 4.280 ;
        RECT 177.750 3.670 180.130 4.280 ;
        RECT 180.970 3.670 183.350 4.280 ;
        RECT 184.190 3.670 186.570 4.280 ;
        RECT 187.410 3.670 193.010 4.280 ;
        RECT 193.850 3.670 205.890 4.280 ;
        RECT 206.730 3.670 209.110 4.280 ;
        RECT 209.950 3.670 212.330 4.280 ;
        RECT 213.170 3.670 215.550 4.280 ;
        RECT 216.390 3.670 218.770 4.280 ;
        RECT 219.610 3.670 221.990 4.280 ;
        RECT 222.830 3.670 261.650 4.280 ;
      LAYER met3 ;
        RECT 3.990 256.040 262.645 264.005 ;
        RECT 4.400 254.640 262.645 256.040 ;
        RECT 3.990 228.840 262.645 254.640 ;
        RECT 4.400 227.440 262.245 228.840 ;
        RECT 3.990 225.440 262.645 227.440 ;
        RECT 4.400 224.040 262.245 225.440 ;
        RECT 3.990 222.040 262.645 224.040 ;
        RECT 4.400 220.640 262.245 222.040 ;
        RECT 3.990 218.640 262.645 220.640 ;
        RECT 4.400 217.240 262.245 218.640 ;
        RECT 3.990 215.240 262.645 217.240 ;
        RECT 4.400 213.840 262.645 215.240 ;
        RECT 3.990 211.840 262.645 213.840 ;
        RECT 4.400 210.440 262.645 211.840 ;
        RECT 3.990 208.440 262.645 210.440 ;
        RECT 4.400 207.040 262.645 208.440 ;
        RECT 3.990 205.040 262.645 207.040 ;
        RECT 4.400 203.640 262.245 205.040 ;
        RECT 3.990 201.640 262.645 203.640 ;
        RECT 4.400 200.240 262.245 201.640 ;
        RECT 3.990 198.240 262.645 200.240 ;
        RECT 4.400 196.840 262.245 198.240 ;
        RECT 3.990 194.840 262.645 196.840 ;
        RECT 4.400 193.440 262.645 194.840 ;
        RECT 3.990 191.440 262.645 193.440 ;
        RECT 4.400 190.040 262.245 191.440 ;
        RECT 3.990 188.040 262.645 190.040 ;
        RECT 4.400 186.640 262.245 188.040 ;
        RECT 3.990 184.640 262.645 186.640 ;
        RECT 4.400 183.240 262.245 184.640 ;
        RECT 3.990 181.240 262.645 183.240 ;
        RECT 3.990 179.840 262.245 181.240 ;
        RECT 3.990 177.840 262.645 179.840 ;
        RECT 3.990 176.440 262.245 177.840 ;
        RECT 3.990 171.040 262.645 176.440 ;
        RECT 3.990 169.640 262.245 171.040 ;
        RECT 3.990 167.640 262.645 169.640 ;
        RECT 4.400 166.240 262.645 167.640 ;
        RECT 3.990 164.240 262.645 166.240 ;
        RECT 4.400 162.840 262.245 164.240 ;
        RECT 3.990 160.840 262.645 162.840 ;
        RECT 4.400 159.440 262.245 160.840 ;
        RECT 3.990 157.440 262.645 159.440 ;
        RECT 4.400 156.040 262.245 157.440 ;
        RECT 3.990 154.040 262.645 156.040 ;
        RECT 4.400 152.640 262.645 154.040 ;
        RECT 3.990 150.640 262.645 152.640 ;
        RECT 4.400 149.240 262.245 150.640 ;
        RECT 3.990 147.240 262.645 149.240 ;
        RECT 4.400 145.840 262.245 147.240 ;
        RECT 3.990 143.840 262.645 145.840 ;
        RECT 4.400 142.440 262.245 143.840 ;
        RECT 3.990 140.440 262.645 142.440 ;
        RECT 4.400 139.040 262.245 140.440 ;
        RECT 3.990 137.040 262.645 139.040 ;
        RECT 4.400 135.640 262.245 137.040 ;
        RECT 3.990 133.640 262.645 135.640 ;
        RECT 4.400 132.240 262.245 133.640 ;
        RECT 3.990 130.240 262.645 132.240 ;
        RECT 4.400 128.840 262.245 130.240 ;
        RECT 3.990 126.840 262.645 128.840 ;
        RECT 4.400 125.440 262.245 126.840 ;
        RECT 3.990 123.440 262.645 125.440 ;
        RECT 4.400 122.040 262.245 123.440 ;
        RECT 3.990 120.040 262.645 122.040 ;
        RECT 4.400 118.640 262.245 120.040 ;
        RECT 3.990 116.640 262.645 118.640 ;
        RECT 4.400 115.240 262.245 116.640 ;
        RECT 3.990 113.240 262.645 115.240 ;
        RECT 4.400 111.840 262.245 113.240 ;
        RECT 3.990 109.840 262.645 111.840 ;
        RECT 4.400 108.440 262.245 109.840 ;
        RECT 3.990 106.440 262.645 108.440 ;
        RECT 4.400 105.040 262.245 106.440 ;
        RECT 3.990 103.040 262.645 105.040 ;
        RECT 4.400 101.640 262.245 103.040 ;
        RECT 3.990 99.640 262.645 101.640 ;
        RECT 4.400 98.240 262.245 99.640 ;
        RECT 3.990 96.240 262.645 98.240 ;
        RECT 4.400 94.840 262.245 96.240 ;
        RECT 3.990 92.840 262.645 94.840 ;
        RECT 4.400 91.440 262.245 92.840 ;
        RECT 3.990 89.440 262.645 91.440 ;
        RECT 4.400 88.040 262.645 89.440 ;
        RECT 3.990 82.640 262.645 88.040 ;
        RECT 4.400 81.240 262.645 82.640 ;
        RECT 3.990 79.240 262.645 81.240 ;
        RECT 3.990 77.840 262.245 79.240 ;
        RECT 3.990 75.840 262.645 77.840 ;
        RECT 4.400 74.440 262.245 75.840 ;
        RECT 3.990 69.040 262.645 74.440 ;
        RECT 3.990 67.640 262.245 69.040 ;
        RECT 3.990 65.640 262.645 67.640 ;
        RECT 3.990 64.240 262.245 65.640 ;
        RECT 3.990 10.715 262.645 64.240 ;
      LAYER met4 ;
        RECT 26.975 13.095 174.240 235.105 ;
        RECT 176.640 13.095 177.540 235.105 ;
        RECT 179.940 13.095 249.945 235.105 ;
  END
END dff_ram_8x72
END LIBRARY

